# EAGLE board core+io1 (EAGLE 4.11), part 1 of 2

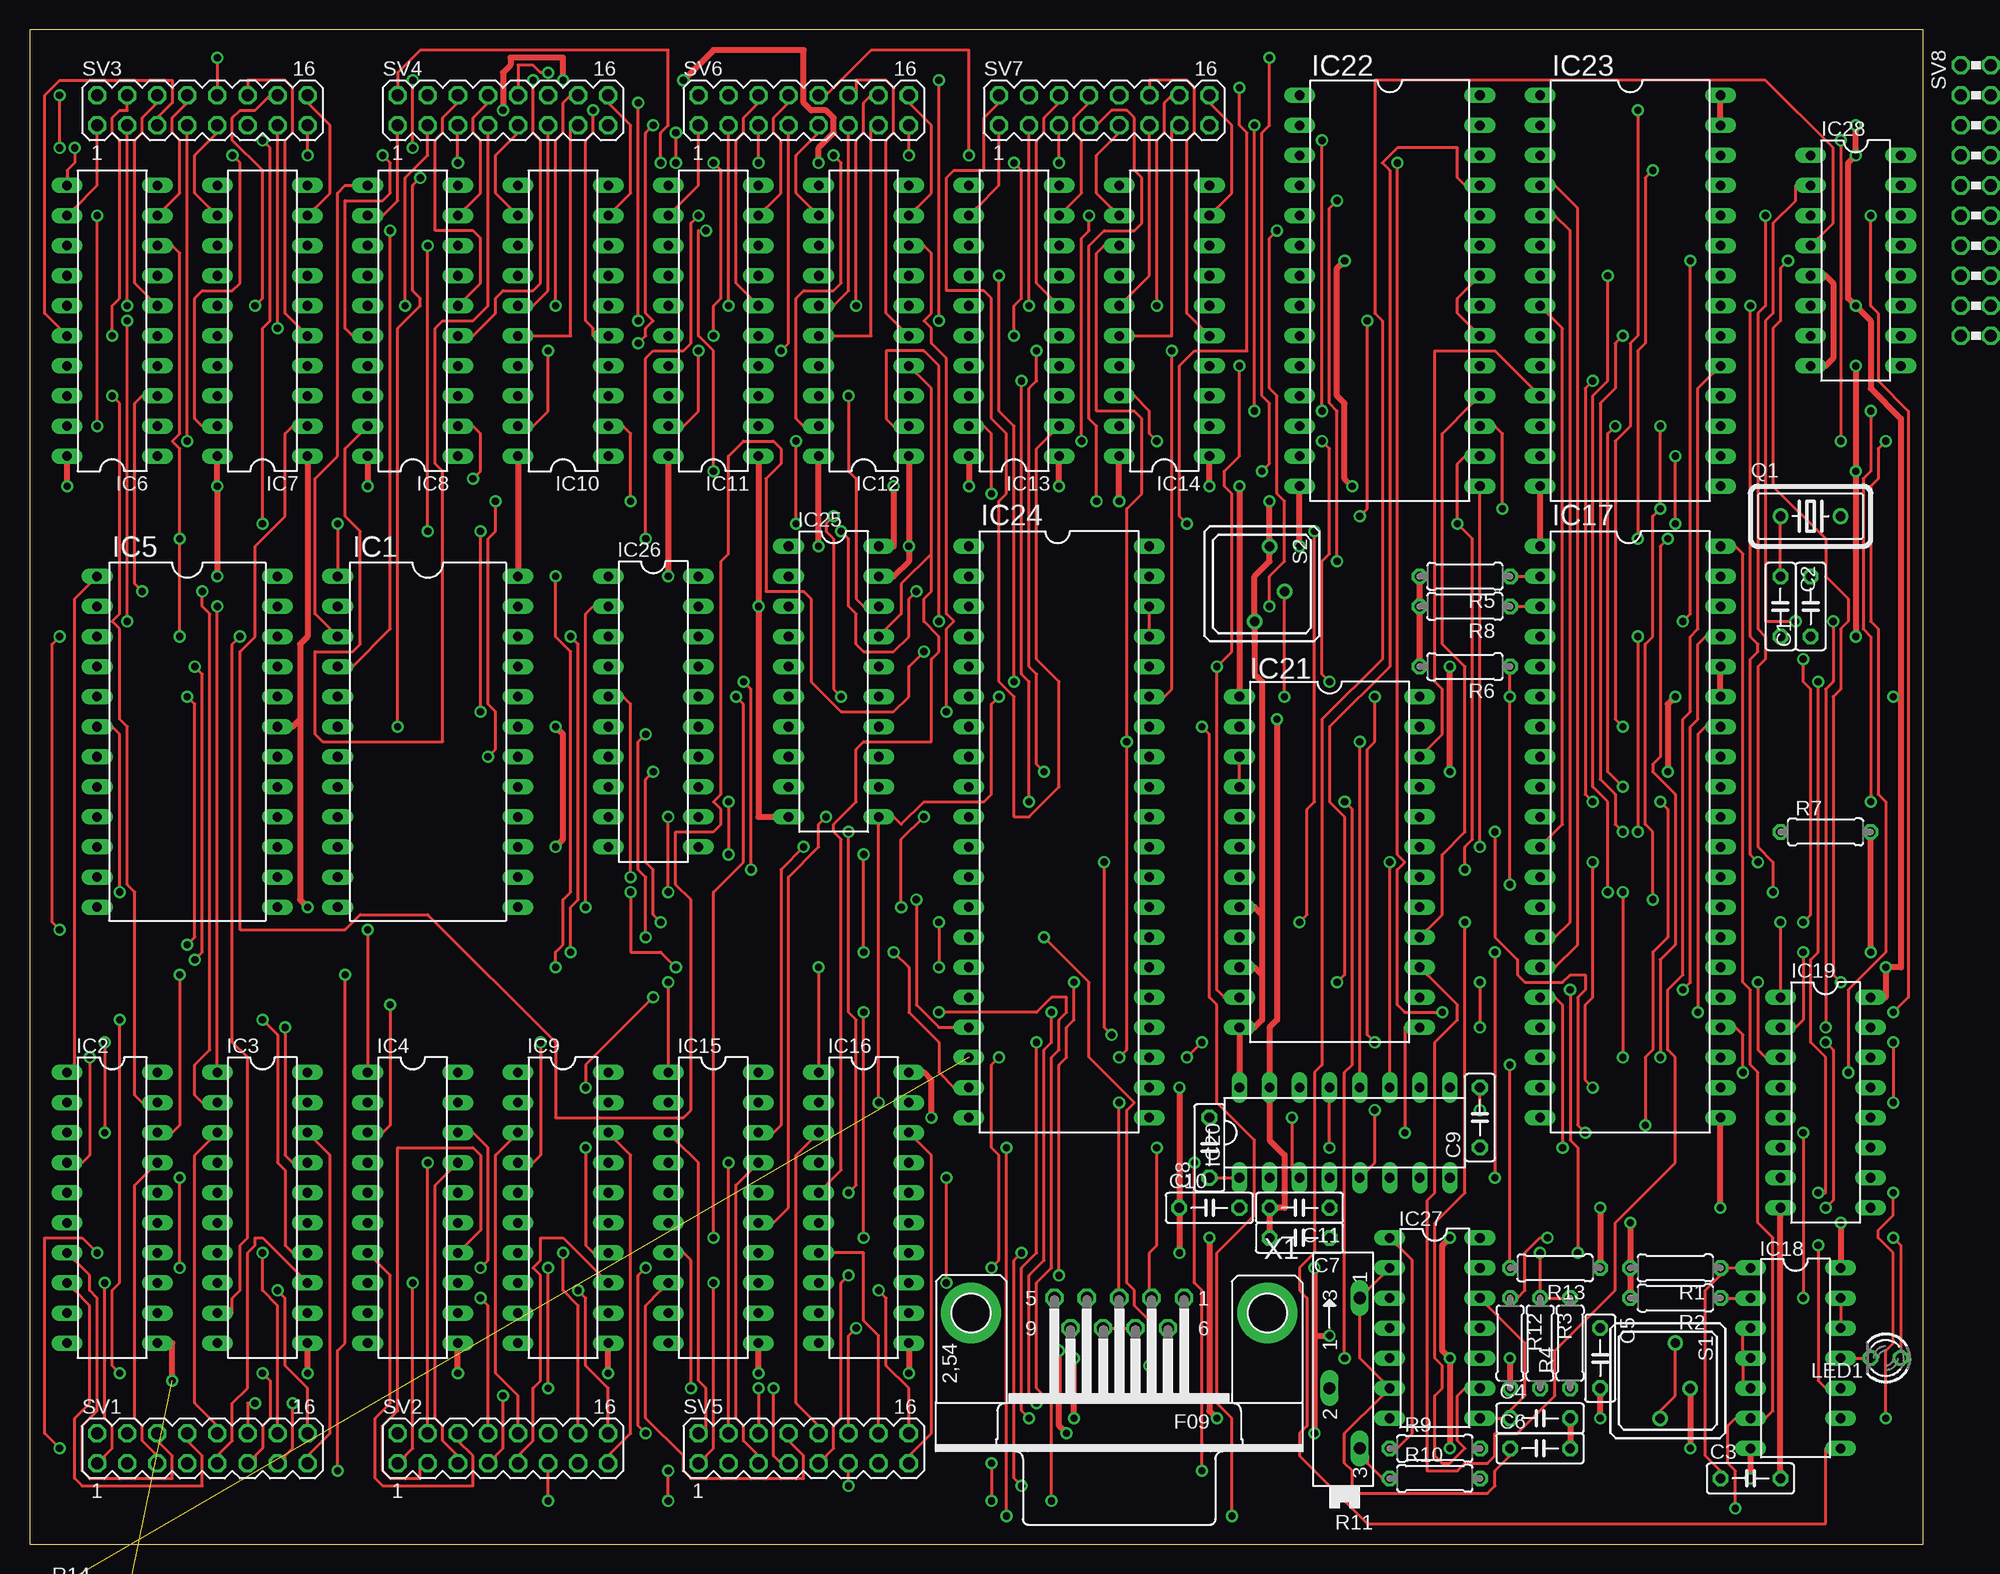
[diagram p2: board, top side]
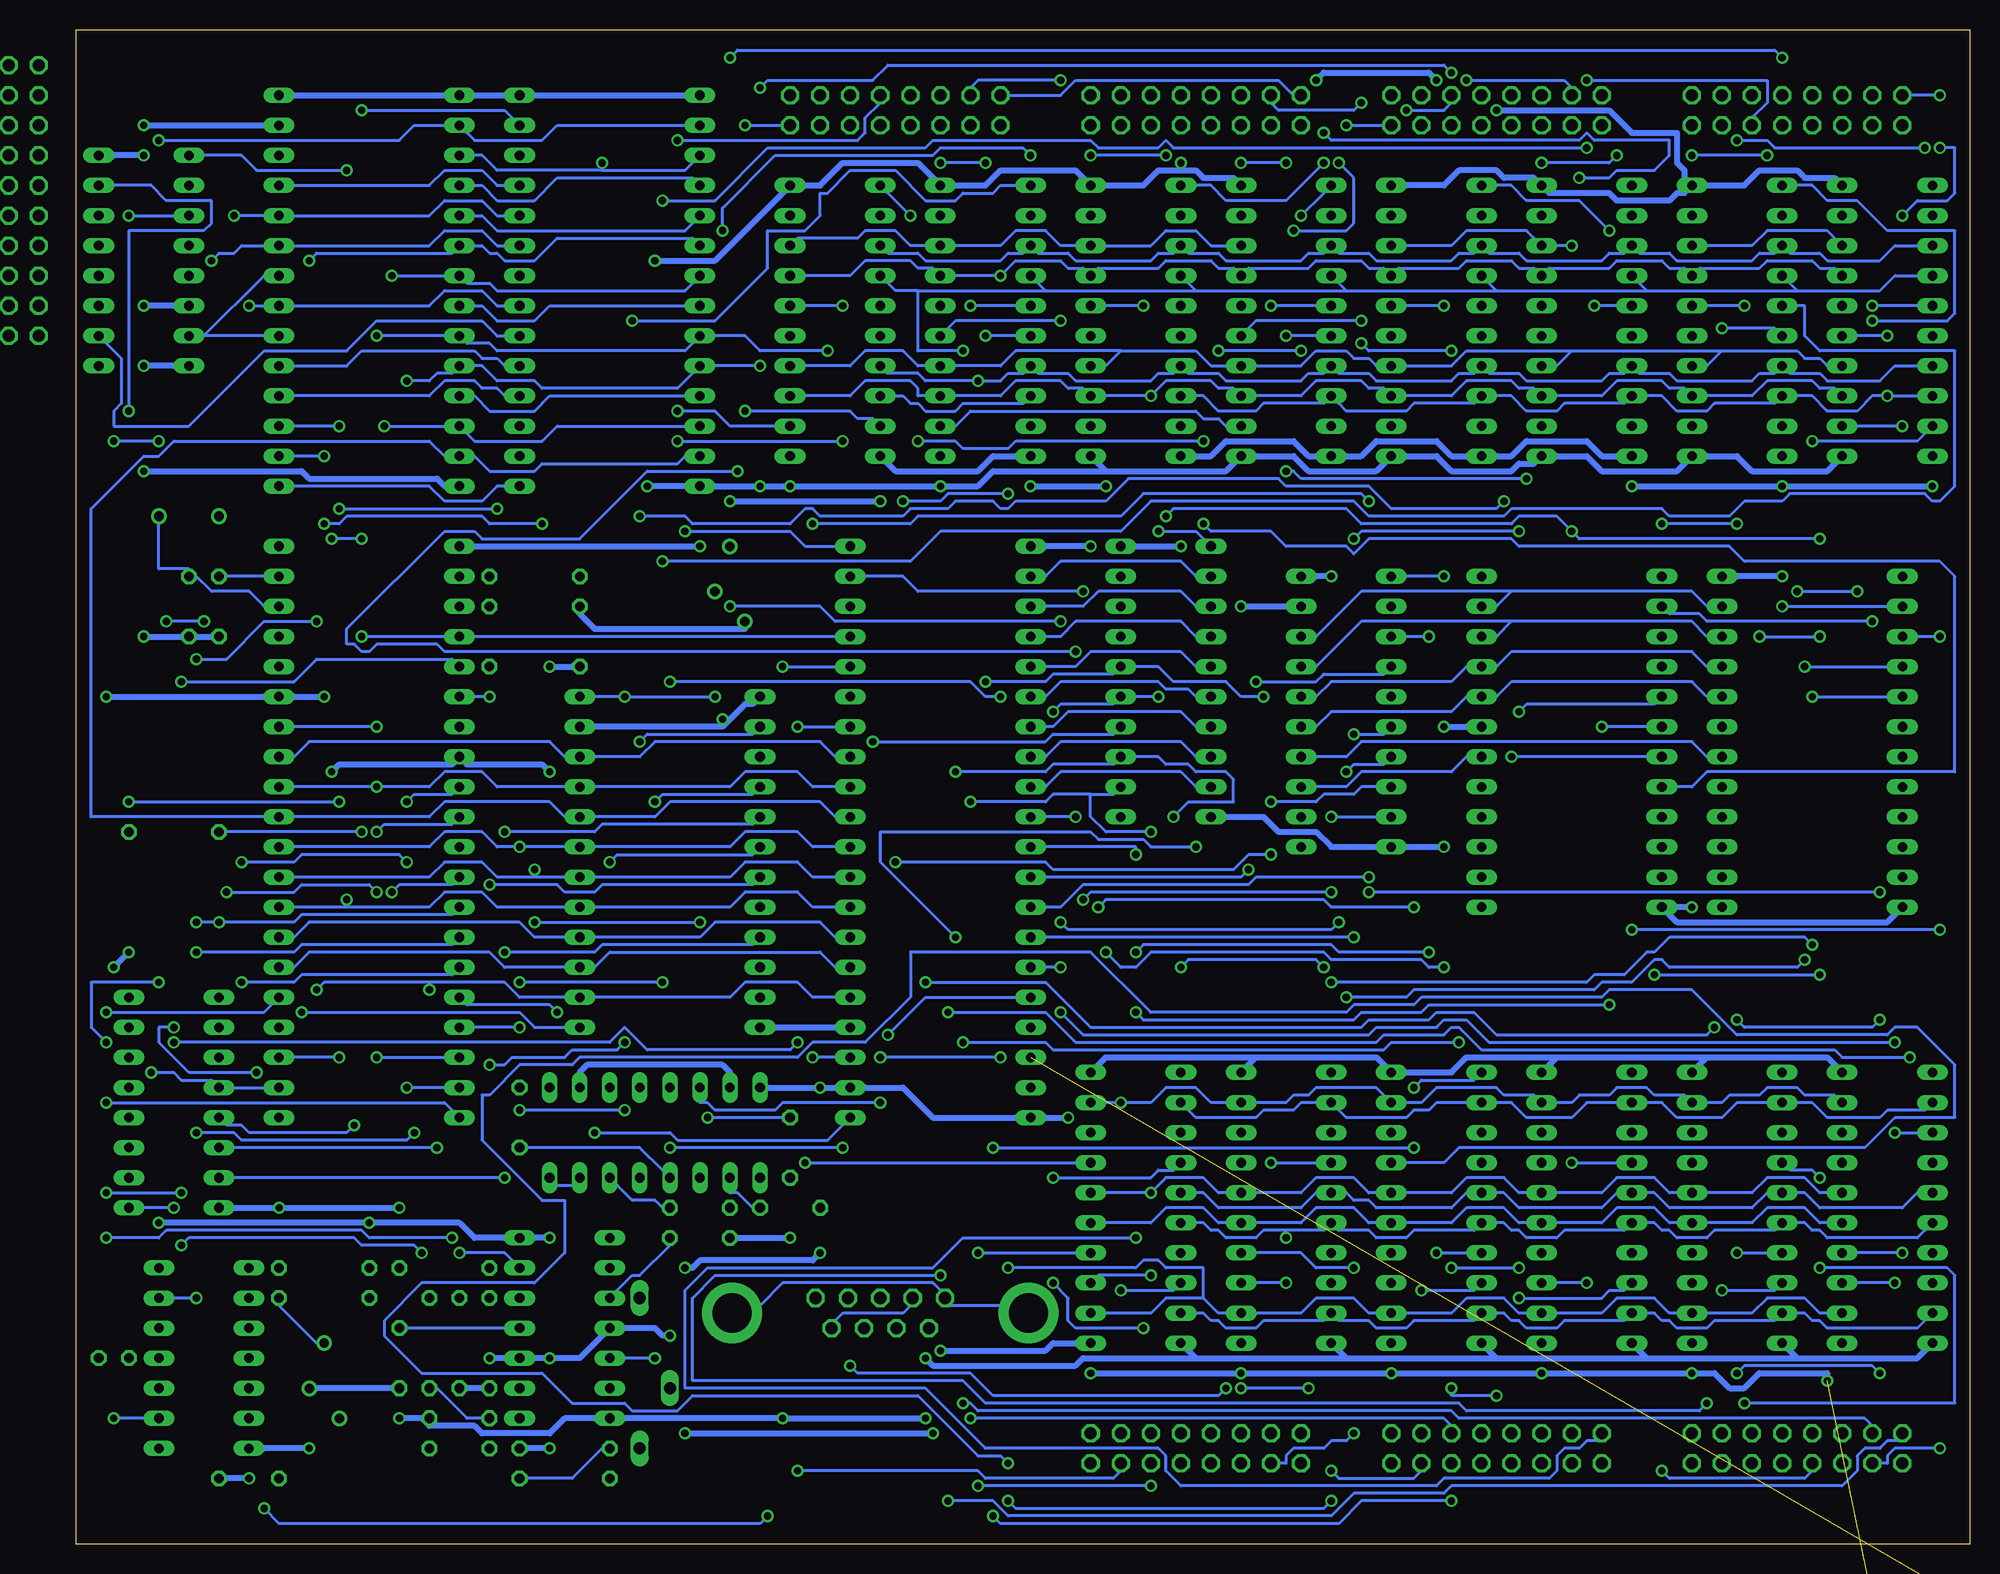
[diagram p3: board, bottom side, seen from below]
Size 160 x 127.94 mm. Coordinates in mm from the lower left corner, seen from the top.
Outline: 0,0 160,0 160,127.94 0,127.94 0,0
Copper layers (1*16): Top 0.035mm / dielectric 1.5mm / Bottom 0.035mm
Design rules "default": minimum track width 10mil, minimum drill 24mil, track to track 8mil, track to pad 8mil, pad to pad 8mil, via to via 8mil, smd to smd 8mil, copper to edge 40mil, drill to drill 8mil, minimum pad ring 10mil, minimum via ring 8mil, stop-mask expansion 4mil, vias tented up to drill 0mil, thermal gap 10mil
Net classes: 1 Power: width 0.508 mm, drill 0.254 mm, clearance 0.254 mm

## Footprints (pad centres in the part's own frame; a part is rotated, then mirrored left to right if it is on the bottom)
C050-025X075 = drill 0.813 octagon: 1 -2.54,0; 2 2.54,0
DIL24-6 = drill 0.813 long: 1 -13.97,-7.62; 2 -11.43,-7.62; 3 -8.89,-7.62; 4 -6.35,-7.62; 5 -3.81,-7.62; 6 -1.27,-7.62; 7 1.27,-7.62; 8 3.81,-7.62; 9 6.35,-7.62; 10 8.89,-7.62; 11 11.43,-7.62; 12 13.97,-7.62; 13 13.97,7.62; 14 11.43,7.62; 15 8.89,7.62; 16 6.35,7.62; 17 3.81,7.62; 18 1.27,7.62; 19 -1.27,7.62; 20 -3.81,7.62; 21 -6.35,7.62; 22 -8.89,7.62; 23 -11.43,7.62; 24 -13.97,7.62
DIL20 = drill 0.813 long: 1 -11.43,-3.81; 2 -8.89,-3.81; 3 -6.35,-3.81; 4 -3.81,-3.81; 5 -1.27,-3.81; 6 1.27,-3.81; 7 3.81,-3.81; 8 6.35,-3.81; 9 8.89,-3.81; 10 11.43,-3.81; 11 11.43,3.81; 12 8.89,3.81; 13 6.35,3.81; 14 3.81,3.81; 15 1.27,3.81; 16 -1.27,3.81; 17 -3.81,3.81; 18 -6.35,3.81; 19 -8.89,3.81; 20 -11.43,3.81
DIL40 = drill 0.813 long: 1 -24.13,-7.62; 2 -21.59,-7.62; 3 -19.05,-7.62; 4 -16.51,-7.62; 5 -13.97,-7.62; 6 -11.43,-7.62; 7 -8.89,-7.62; 8 -6.35,-7.62; 9 -3.81,-7.62; 10 -1.27,-7.62; 11 1.27,-7.62; 12 3.81,-7.62; 13 6.35,-7.62; 14 8.89,-7.62; 15 11.43,-7.62; 16 13.97,-7.62; 17 16.51,-7.62; 18 19.05,-7.62; 19 21.59,-7.62; 20 24.13,-7.62; 21 24.13,7.62; 22 21.59,7.62; 23 19.05,7.62; 24 16.51,7.62; 25 13.97,7.62; 26 11.43,7.62; 27 8.89,7.62; 28 6.35,7.62; 29 3.81,7.62; 30 1.27,7.62; 31 -1.27,7.62; 32 -3.81,7.62; 33 -6.35,7.62; 34 -8.89,7.62; 35 -11.43,7.62; 36 -13.97,7.62; 37 -16.51,7.62; 38 -19.05,7.62; 39 -21.59,7.62; 40 -24.13,7.62
DIL14 = drill 0.813 long: 1 -7.62,-3.81; 2 -5.08,-3.81; 3 -2.54,-3.81; 4 0,-3.81; 5 2.54,-3.81; 6 5.08,-3.81; 7 7.62,-3.81; 8 7.62,3.81; 9 5.08,3.81; 10 2.54,3.81; 11 0,3.81; 12 -2.54,3.81; 13 -5.08,3.81; 14 -7.62,3.81
DIL16 = drill 0.813 long: 1 -8.89,-3.81; 2 -6.35,-3.81; 3 -3.81,-3.81; 4 -1.27,-3.81; 5 1.27,-3.81; 6 3.81,-3.81; 7 6.35,-3.81; 8 8.89,-3.81; 9 8.89,3.81; 10 6.35,3.81; 11 3.81,3.81; 12 1.27,3.81; 13 -1.27,3.81; 14 -3.81,3.81; 15 -6.35,3.81; 16 -8.89,3.81
DIL24 = drill 0.813 long: 1 -13.97,-7.62; 2 -11.43,-7.62; 3 -8.89,-7.62; 4 -6.35,-7.62; 5 -3.81,-7.62; 6 -1.27,-7.62; 7 1.27,-7.62; 8 3.81,-7.62; 9 6.35,-7.62; 10 8.89,-7.62; 11 11.43,-7.62; 12 13.97,-7.62; 13 13.97,7.62; 14 11.43,7.62; 15 8.89,7.62; 16 6.35,7.62; 17 3.81,7.62; 18 1.27,7.62; 19 -1.27,7.62; 20 -3.81,7.62; 21 -6.35,7.62; 22 -8.89,7.62; 23 -11.43,7.62; 24 -13.97,7.62
DIL28 = drill 0.813 long: 1 -16.51,-7.62; 2 -13.97,-7.62; 3 -11.43,-7.62; 4 -8.89,-7.62; 5 -6.35,-7.62; 6 -3.81,-7.62; 7 -1.27,-7.62; 8 1.27,-7.62; 9 3.81,-7.62; 10 6.35,-7.62; 11 8.89,-7.62; 12 11.43,-7.62; 13 13.97,-7.62; 14 16.51,-7.62; 15 16.51,7.62; 16 13.97,7.62; 17 11.43,7.62; 18 8.89,7.62; 19 6.35,7.62; 20 3.81,7.62; 21 1.27,7.62; 22 -1.27,7.62; 23 -3.81,7.62; 24 -6.35,7.62; 25 -8.89,7.62; 26 -11.43,7.62; 27 -13.97,7.62; 28 -16.51,7.62
LED3MM = drill 0.813 octagon: A -1.27,0; K 1.27,0
HC18U-V = drill 0.813 round: 1 -2.54,0; 2 2.54,0
0207/7 = drill 0.813 octagon: 1 -3.81,0; 2 3.81,0
SP19L = drill 1.016 long: A 5.715,-1.27; E -6.985,-1.27; S -1.905,1.27
RDT1034 = drill 0.8 round: A 3.175,-0.635; A1 -3.175,0.635; B 0.65,1.9
MA08-2 = drill 1.016 octagon: 1 -8.89,-1.27; 2 -8.89,1.27; 3 -6.35,-1.27; 4 -6.35,1.27; 5 -3.81,-1.27; 6 -3.81,1.27; 7 -1.27,-1.27; 8 -1.27,1.27; 9 1.27,-1.27; 10 1.27,1.27; 11 3.81,-1.27; 12 3.81,1.27; 13 6.35,-1.27; 14 6.35,1.27; 15 8.89,-1.27; 16 8.89,1.27
MA10-2W = drill 1.016 octagon: 1 -11.43,-1.27; 2 -11.43,1.27; 3 -8.89,-1.27; 4 -8.89,1.27; 5 -6.35,-1.27; 6 -6.35,1.27; 7 -3.81,-1.27; 8 -3.81,1.27; 9 -1.27,-1.27; 10 -1.27,1.27; 11 1.27,-1.27; 12 1.27,1.27; 13 3.81,-1.27; 14 3.81,1.27; 15 6.35,-1.27; 16 6.35,1.27; 17 8.89,-1.27; 18 8.89,1.27; 19 11.43,-1.27; 20 11.43,1.27
F09HP = drill 1.016 octagon: 1 -5.486,-1.27; 2 -2.743,-1.27; 3 0,-1.27; 4 2.743,-1.27; 5 5.486,-1.27; 6 -4.115,1.27; 7 -1.372,1.27; 8 1.372,1.27; 9 4.115,1.27 | drill 3.302 pad 5.08 round: G1 -12.522,0; G2 12.522,0

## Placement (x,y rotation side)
C1  27pf  [C050-025X075]  150.49,79.21 90 top
C2  27pf  [C050-025X075]  147.95,79.21 270 top
C3  22uf  [C050-025X075]  145.41,5.55 0 top
C4  0.1uf  [C050-025X075]  127.63,10.63 0 top
C5  10uf  [C050-025X075]  132.71,15.71 270 top
C6  330pf  [C050-025X075]  127.63,8.09 0 top
C7  10uf  [C050-025X075]  107.31,25.87 180 top
C8  0.1uf  [C050-025X075]  99.69,33.49 90 top
C9  0.1uf  [C050-025X075]  122.55,36.03 90 top
C10  0.1uf  [C050-025X075]  99.69,28.41 0 top
C11  0.1uf  [C050-025X075]  107.31,28.41 180 top
IC1  74154N  [DIL24-6]  33.65,67.78 270 top
IC2  74LS373N  [DIL20]  6.98,28.41 270 top
IC3  74LS373N  [DIL20]  19.68,28.41 270 top
IC4  74LS373N  [DIL20]  32.38,28.41 270 top
IC5  74154N  [DIL24-6]  13.33,67.78 270 top
IC6  74LS374N  [DIL20]  6.98,103.34 90 top
IC7  74LS374N  [DIL20]  19.68,103.34 90 top
IC8  74LS374N  [DIL20]  32.38,103.34 90 top
IC9  74LS373N  [DIL20]  45.08,28.41 270 top
IC10  74LS374N  [DIL20]  45.08,103.34 90 top
IC11  74LS374N  [DIL20]  57.78,103.34 90 top
IC12  74LS374N  [DIL20]  70.48,103.34 90 top
IC13  74LS374N  [DIL20]  83.18,103.34 90 top
IC14  74LS374N  [DIL20]  95.88,103.34 90 top
IC15  74LS373N  [DIL20]  57.78,28.41 270 top
IC16  74LS373N  [DIL20]  70.48,28.41 270 top
IC17  [DIL40]  135.25,60.16 270 top
IC18  74LS00N  [DIL14]  149.22,15.71 270 top
IC19  74LS138N  [DIL16]  151.76,37.3 270 top
IC20  MAX232  [DIL16]  111.12,34.76 0 top
IC21  [DIL24]  109.85,57.62 270 top
IC22  5565  [DIL28]  114.93,105.88 270 top
IC23  2764  [DIL28]  135.25,105.88 270 top
IC24  [DIL40]  86.99,60.16 270 top
IC25  74LS245N  [DIL20]  67.94,72.86 270 top
IC26  74LS245N  [DIL20]  52.7,70.32 270 top
IC27  LM556N  [DIL14]  118.74,18.25 270 top
IC28  74LS138N  [DIL16]  154.3,108.42 270 top
LED1  [LED3MM]  156.84,15.71 180 top
Q1  4Mhz  [HC18U-V]  150.49,86.83 0 top
R1  10K  [0207/7]  139.06,23.33 180 top
R2  10K  [0207/7]  139.06,20.79 180 top
R3  100K  [0207/7]  127.63,16.98 270 top
R4  100K  [0207/7]  130.17,16.98 90 top
R5  3.3K  [0207/7]  121.28,81.75 180 top
R6  3.3K  [0207/7]  121.28,74.13 180 top
R7  3.3K  [0207/7]  151.76,60.16 0 top
R8  3.3K  [0207/7]  121.28,79.21 180 top
R9  1.8K  [0207/7]  118.74,8.09 0 top
R10  10K  [0207/7]  118.74,5.55 0 top
R11  10K  [SP19L]  111.12,15.08 90 top
R12  270  [0207/7]  125.09,16.98 270 top
R13  1K  [0207/7]  128.9,23.33 180 top
R14  3.3K  [0207/7]  not placed on the board
S1  RESET  [RDT1034]  138.42,13.81 270 top
S2  DEBUG  [RDT1034]  104.13,81.11 270 top
SV1  [MA08-2]  14.6,8.09 0 top
SV2  [MA08-2]  40,8.09 0 top
SV3  [MA08-2]  14.6,121.12 0 top
SV4  [MA08-2]  40,121.12 0 top
SV5  [MA08-2]  65.4,8.09 0 top
SV6  [MA08-2]  65.4,121.12 0 top
SV7  [MA08-2]  90.8,121.12 0 top
SV8  [MA10-2W]  not placed on the board
X1  [F09HP]  92.07,19.52 180 top

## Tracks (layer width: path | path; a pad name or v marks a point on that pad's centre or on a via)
A00  (via drill 0.61)
  Top 0.254: IC21.11 100.96,46.19 100.32,46.82 v100.32,74.13 101.59,75.4 101.59,88.73 100.96,89.37 100.96,90.64 102.23,91.91 v102.23,99.53 | v132.07,62.7 131.44,63.34 131.44,97.62 v132.07,98.26
  Bottom 0.254: v100.32,74.13 95.88,74.13 IC24.36 | v132.07,62.7 131.44,63.34 128.27,63.34 IC17.9 | v132.07,98.26 130.17,98.26 129.53,98.89 128.27,98.89 IC23.10 126.36,99.53 125.72,99.53 124.45,98.26 121.28,98.26 120.64,97.62 109.21,97.62 107.94,98.89 IC22.10 106.04,99.53 v102.23,99.53
A01  (via drill 0.61)
  Top 0.254: v96.52,100.8 96.52,72.22 95.88,71.59 IC24.35 | v134.62,60.16 133.98,60.8 133.98,63.34 132.71,64.61 132.71,96.36 133.98,97.62 133.98,101.44 v134.62,102.07
  Bottom 0.254: v96.52,100.8 102.23,100.8 103.5,102.07 106.04,102.07 IC22.9 107.94,101.44 108.58,100.8 124.45,100.8 125.09,101.44 126.99,101.44 IC23.9 128.9,102.07 v134.62,102.07 | v134.62,60.16 133.98,60.8 128.27,60.8 IC17.10
A02
  Top 0.254: IC17.11 128.27,59.52 129.53,60.8 129.53,102.7 128.27,103.97 IC23.8
  Bottom 0.254: IC22.8 108.58,104.61 120.01,104.61 121.28,103.34 124.45,103.34 125.72,104.61 126.36,104.61 IC23.8
A03  (via drill 0.61)
  Top 0.254: v133.34,55.08 133.34,62.7 132.07,63.97 132.07,96.99 133.34,98.26 v133.34,107.15
  Bottom 0.254: v133.34,55.08 132.71,55.71 128.27,55.71 IC17.12 | v133.34,107.15 128.9,107.15 IC23.7 126.99,106.52 125.09,106.52 124.45,105.88 108.58,105.88 107.94,106.52 IC22.7
A04  (via drill 0.61)
  Top 0.254: v147.95,52.54 147.95,46.82 IC19.1 | v140.33,108.42 140.33,78.58 v139.69,77.94 | v149.85,74.77 149.85,72.86 150.49,72.22 150.49,53.17 v149.85,52.54
  Bottom 0.254: IC22.6 107.94,110.33 119.38,110.33 121.28,108.42 123.82,108.42 124.45,109.05 125.09,109.05 125.72,109.69 126.36,109.69 IC23.6 128.27,109.05 139.69,109.05 v140.33,108.42 | IC17.13 128.27,53.17 140.97,53.17 141.6,52.54 v147.95,52.54 v149.85,52.54 | v139.69,77.94 144.14,77.94 147.31,74.77 v149.85,74.77
A05  (via drill 0.61)
  Top 0.254: IC23.5 128.9,112.23 130.17,110.96 130.17,52.54 128.9,51.27 IC17.14 | v149.85,50 149.85,44.28 149.22,43.65 IC19.2
  Bottom 0.254: v149.85,50 141.6,50 140.97,50.63 128.27,50.63 IC17.14 | IC22.5 107.94,111.59 108.58,110.96 124.45,110.96 125.72,112.23 126.36,112.23 IC23.5
A06  (via drill 0.61)
  Top 0.254: IC23.4 128.9,114.77 130.81,112.86 130.81,50.63 128.9,48.73 IC17.15 | v146.04,47.46 146.04,41.74 146.68,41.11 IC19.3
  Bottom 0.254: v146.04,47.46 141.6,47.46 140.97,48.09 128.27,48.09 IC17.15 | IC22.4 107.94,115.41 119.38,115.41 121.28,113.5 124.45,113.5 125.72,114.77 126.36,114.77 IC23.4
A07  (via drill 0.61)
  Top 0.254: v129.53,33.49 129.53,45.55 128.9,46.19 IC17.16 | v115.56,116.67 115.56,58.25 116.2,57.62 115.56,56.98 115.56,45.55 116.2,44.92 v119.38,44.92
  Bottom 0.254: 115.56,116.04 124.45,116.04 125.72,117.31 126.36,117.31 IC23.3 | 115.56,116.04 108.58,116.04 107.94,116.67 IC22.3 | v129.53,33.49 146.68,33.49 IC19.6 | v115.56,116.67 115.56,116.04 | v119.38,44.92 120.01,45.55 126.99,45.55 IC17.16
A08  (via drill 0.61)
  Top 0.254: v122.55,47.46 v122.55,43.65 | v110.48,47.46 111.12,48.09 111.12,61.43 109.85,62.7 109.85,69.05 114.93,74.13 114.93,116.04 114.3,116.67 115.56,117.94 120.64,117.94 120.64,115.41 121.28,114.77 IC22.25
  Bottom 0.254: IC23.25 141.6,114.77 130.17,114.77 128.9,116.04 125.72,116.04 124.45,114.77 123.82,114.77 IC22.25 | v122.55,43.65 126.36,43.65 IC17.17 | v110.48,47.46 v122.55,47.46
A09  (via drill 0.61)
  Top 0.254: v134.62,55.08 v134.62,41.11 | v147.31,55.08 147.31,57.62 146.04,58.89 146.04,74.13 146.68,74.77 146.68,76.67 146.04,77.3 146.04,103.97 146.68,104.61 v146.68,112.23
  Bottom 0.254: IC22.24 123.82,112.23 124.45,112.23 125.72,113.5 128.9,113.5 130.17,112.23 141.6,112.23 IC23.24 144.14,112.23 v146.68,112.23 | v134.62,41.11 128.9,41.11 IC17.18 | v134.62,55.08 135.25,55.71 140.97,55.71 141.6,55.08 v147.31,55.08
A10  (via drill 0.61)
  Top 0.254: v132.07,38.57 131.44,39.2 131.44,45.55 132.07,46.19 v132.07,57.62 | v146.04,57.62 145.41,58.25 145.41,74.77 146.04,75.4 146.04,76.03 145.41,76.67 v145.41,104.61
  Bottom 0.254: IC22.21 123.82,104.61 124.45,104.61 125.72,105.88 128.9,105.88 130.17,104.61 141.6,104.61 IC23.21 144.14,104.61 v145.41,104.61 | v132.07,38.57 128.9,38.57 IC17.19 | v132.07,57.62 132.71,58.25 140.97,58.25 141.6,57.62 v146.04,57.62
A11  (via drill 0.61)
  Top 0.254: v157.47,42.38 v157.47,37.3 | v153.03,47.46 152.39,48.09 152.39,71.59 153.03,72.22 153.03,77.3 153.66,77.94 153.66,79.84 151.76,81.75 151.76,84.92 147.31,89.37 147.31,102.7 147.95,103.34 147.95,107.78 v148.59,108.42
  Bottom 0.254: IC22.23 123.82,109.69 124.45,109.69 125.72,110.96 128.9,110.96 130.17,109.69 141.6,109.69 IC23.23 144.14,109.69 146.04,109.69 146.68,109.05 147.95,109.05 v148.59,108.42 | v157.47,37.3 128.9,37.3 128.27,36.66 IC17.20 | v157.47,42.38 158.75,43.65 158.75,47.46 v153.03,47.46
A12  (via drill 0.61)
  Top 0.254: v153.66,39.84 153.66,46.82 156.84,50 156.84,62.7 156.2,63.34 156.2,77.3 155.57,77.94 155.57,89.37 156.2,90 156.2,92.55 v156.84,93.18 | v153.03,118.58 v153.03,93.18
  Bottom 0.254: IC17.22 144.14,38.57 146.68,38.57 IC19.4 148.59,39.2 151.12,39.2 151.76,39.84 v153.66,39.84 | IC22.2 108.58,119.85 119.38,119.85 120.64,118.58 126.36,118.58 126.99,119.22 IC23.2 128.9,119.85 131.44,119.85 132.71,118.58 v153.03,118.58 | v153.03,93.18 v156.84,93.18
A13  (via drill 0.61)
  Top 0.254: v137.79,41.11 137.79,49.37 139.06,50.63 139.06,63.34 137.16,65.24 137.16,65.88 137.79,66.51 137.79,84.29 v138.42,84.92 | v135.88,84.92 135.88,100.8 136.52,101.44 136.52,115.41 v137.16,116.04
  Bottom 0.254: v137.79,41.11 141.6,41.11 IC17.23 | v135.88,84.92 v138.42,84.92 | v137.16,116.04 144.78,116.04 146.04,117.31 149.22,117.31 IC28.1
A14  (via drill 0.61)
  Top 0.254: v144.78,39.84 144.78,43.02 144.14,43.65 IC17.24 | v151.76,43.65 151.76,72.22 152.39,72.86 v152.39,77.94 | v149.22,77.94 146.68,77.94 146.68,103.34 147.31,103.97 147.31,111.59 149.22,113.5 149.22,114.77 IC28.2
  Bottom 0.254: v144.78,39.84 150.49,39.84 153.03,42.38 153.03,43.65 v151.76,43.65 | v149.22,77.94 v152.39,77.94
A15  (via drill 0.61)
  Top 0.254: v157.47,44.92 158.75,46.19 158.75,95.72 156.2,98.26 156.2,103.97 155.57,104.61 v155.57,112.23
  Bottom 0.254: v157.47,44.92 144.14,44.92 143.5,45.55 IC17.25 | v155.57,112.23 151.76,112.23 IC28.3
AB\
  Top 0.254: IC22.20 121.91,102.7 120.64,103.97 120.64,105.25 121.91,106.52 IC22.22
  Bottom 0.254: IC28.10 157.47,101.44 156.2,100.16 156.2,96.36 156.84,95.72 156.84,94.45 150.49,94.45 144.14,100.8 137.16,100.8 134.62,103.34 125.72,103.34 124.45,102.07 123.82,102.07 IC22.20
CB1  (1 unrouted)
D0
  Top 0.254: IC23.11 126.99,97.62 123.82,100.8 118.74,100.8 118.74,72.86 119.38,72.22 119.38,68.41 118.1,67.14 IC21.22
  Bottom 0.254: IC22.11 108.58,96.99 120.01,96.99 121.28,95.72 125.09,95.72 126.36,96.99 IC23.11 | IC24.33 95.88,66.51 97.15,67.78 111.12,67.78 112.39,66.51 116.2,66.51 IC21.22 118.74,66.51 120.01,67.78 140.33,67.78 141.6,66.51 IC17.33
D1  (via drill 0.61)
  Top 0.254: v133.98,94.45 133.34,93.81 133.34,65.24 v134.62,63.97
  Bottom 0.254: IC22.12 108.58,94.45 119.38,94.45 120.64,93.18 126.36,93.18 126.99,93.81 IC23.12 128.9,94.45 v133.98,94.45 | IC24.32 95.88,63.97 97.78,63.97 99.05,65.24 103.5,65.24 104.77,63.97 116.2,63.97 IC21.21 118.74,63.97 124.45,63.97 125.72,65.24 128.9,65.24 130.17,63.97 v134.62,63.97 141.6,63.97 IC17.32
D2
  Bottom 0.254: IC22.13 108.58,91.91 109.21,91.28 120.64,91.28 121.28,90.64 125.09,90.64 126.36,91.91 IC23.13 128.9,91.91 130.17,93.18 151.76,93.18 153.03,91.91 154.3,91.91 158.75,87.47 158.75,61.43 144.14,61.43 IC17.31 141.6,61.43 130.17,61.43 128.9,62.7 120.01,62.7 118.74,61.43 IC21.20 116.2,61.43 111.12,61.43 109.85,62.7 97.15,62.7 95.88,61.43 IC24.31
D3  (via drill 0.61)
  Top 0.254: v122.55,58.89 122.55,88.73 IC22.15
  Bottom 0.254: IC23.15 141.6,89.37 130.17,89.37 128.9,88.1 125.72,88.1 124.45,89.37 123.82,89.37 IC22.15 | IC24.30 95.88,58.89 97.78,58.89 99.05,60.16 103.5,60.16 104.77,58.89 116.2,58.89 IC21.19 118.74,58.89 v122.55,58.89 124.45,58.89 125.72,60.16 128.9,60.16 130.17,58.89 141.6,58.89 IC17.30
D4  (via drill 0.61)
  Top 0.254: v139.06,86.19 v139.06,91.91 | IC22.16 121.28,91.91 120.64,91.28 v120.64,86.19 121.91,84.92 121.91,59.52 121.28,58.89 v121.28,56.98
  Bottom 0.254: v120.64,86.19 125.09,86.19 125.72,86.83 137.16,86.83 137.79,86.19 v139.06,86.19 | v139.06,91.91 141.6,91.91 IC23.16 | IC24.29 95.88,56.35 97.78,56.35 99.05,57.62 103.5,57.62 104.77,56.35 116.2,56.35 IC21.18 118.74,56.35 121.28,56.35 | 121.28,56.35 124.45,56.35 125.72,57.62 128.9,57.62 130.17,56.35 141.6,56.35 IC17.29 | 121.28,56.35 v121.28,56.98
D5  (via drill 0.61)
  Top 0.254: v124.45,87.47 124.45,93.81 123.82,94.45 IC22.17 | v137.79,94.45 v137.79,87.47 137.16,86.83 137.16,76.67 136.52,76.03 136.52,60.8 137.16,60.16 v137.16,54.45
  Bottom 0.254: v137.79,87.47 v124.45,87.47 | v137.79,94.45 141.6,94.45 IC23.17 | IC24.28 95.88,53.81 97.78,53.81 99.05,55.08 103.5,55.08 104.77,53.81 116.2,53.81 IC21.17 118.74,53.81 124.45,53.81 125.72,55.08 128.9,55.08 130.17,53.81 137.16,53.81 | 137.16,53.81 141.6,53.81 IC17.28 | 137.16,53.81 v137.16,54.45
D6
  Top 0.254: IC22.18 121.91,96.36 119.38,93.81 119.38,76.03 121.28,74.13 121.28,60.16 119.38,58.25 119.38,53.17 118.1,51.91 IC21.16
  Bottom 0.254: IC22.18 123.82,96.99 124.45,97.62 125.72,97.62 126.36,98.26 128.9,98.26 130.17,96.99 141.6,96.99 IC23.18 | IC24.27 95.88,51.27 97.15,52.54 106.04,52.54 107.31,51.27 116.2,51.27 IC21.16 118.74,51.27 121.28,51.27 122.55,52.54 140.33,52.54 141.6,51.27 IC17.27
D7
  Top 0.254: IC23.19 142.23,98.89 140.97,97.62 140.97,77.3 140.33,76.67 140.33,70.32 139.69,69.69 139.69,48.09 138.42,46.82 138.42,41.74 139.06,41.11 139.06,32.22 133.98,27.14 133.98,21.42 128.9,16.34 128.9,12.54 125.72,9.36 123.82,9.36 123.82,7.46 123.19,6.82 121.28,6.82 120.64,6.18 118.1,6.18 118.1,29.04 118.74,29.68 118.74,42.38 120.64,44.28 120.64,45.55 118.1,48.09 IC21.15
  Bottom 0.254: IC22.19 123.82,99.53 124.45,100.16 125.72,100.16 126.36,100.8 135.88,100.8 137.16,99.53 141.6,99.53 IC23.19 | IC24.26 95.88,48.73 97.15,50 114.93,50 116.2,48.73 IC21.15 118.74,48.73 123.82,48.73 125.09,50 140.33,50 141.6,48.73 IC17.26
E  (via drill 0.61)
  Top 0.254: v151.12,25.23 151.12,13.81 151.76,13.17 IC18.10 | v130.81,24.6 130.81,33.49 130.17,34.12 v130.17,46.82 | v139.69,46.82 140.33,47.46 140.33,69.05 140.97,69.69 140.97,76.03 141.6,76.67 IC17.37
  Bottom 0.254: IC24.25 95.88,46.19 97.78,46.19 99.05,47.46 103.5,47.46 104.77,46.19 116.2,46.19 IC21.14 118.74,46.19 122.55,46.19 123.82,47.46 130.17,47.46 | v151.12,25.23 150.49,25.87 136.52,25.87 135.88,25.23 131.44,25.23 v130.81,24.6 | 130.17,47.46 v130.17,46.82 | v139.69,46.82 139.06,47.46 130.17,47.46
EF\
  Bottom 0.254: 149.22,102.07 144.14,102.07 IC23.20 | 149.22,102.07 IC28.7 149.22,102.07 | 149.22,102.07 144.14,107.15 IC23.22
GND  (via drill 0.61)
  Top 0.508: 22.86,69.69 22.22,69.05 IC5.19 | 22.86,69.69 22.86,76.03 23.49,76.67 23.49,91.28 IC7.1 | v23.49,53.81 22.86,54.45 22.86,69.69 | IC25.19 73.02,81.75 74.29,83.02 v74.29,84.29 74.29,91.28 IC12.1 | v44.45,58.89 45.08,59.52 45.08,68.41 v44.45,69.05 | IC11.1 61.59,91.28 v61.59,79.21 61.59,61.43 62.86,61.43 IC25.10 | v40,121.12 40,124.3 40.64,124.93 40.64,125.56 45.08,125.56 v45.08,123.66 | v55.24,123.66 57.78,126.2 65.4,126.2 65.4,121.75 66.03,121.12 67.3,121.12 67.94,120.48 67.94,119.22 66.67,117.94 v66.67,116.67 | v145.41,5.55 145.41,7.46 IC18.7 | C6.2 130.17,8.73 130.17,10 C4.2 | v132.71,10.63 132.71,12.54 C5.2 | v140.33,8.09 140.33,12.54 S1.B | v132.71,28.41 132.71,23.96 R13.1 | v142.87,28.41 142.87,35.39 IC17.21 | C3.2 147.95,6.18 147.95,27.77 IC19.8 | C7.2 104.77,26.5 104.77,27.77 C11.2 105.41,28.41 106.04,28.41 106.04,32.85 104.77,34.12 104.77,37.3 IC20.15 104.77,39.84 104.77,43.65 105.41,44.28 v105.41,69.69 | v100.32,10.63 99.69,11.27 v99.69,25.87 | IC28.8 151.76,99.53 152.39,100.16 152.39,106.52 151.76,107.15 IC28.5 | v154.3,99.53 v154.3,90.64 v154.3,76.67 | IC17.1 127.63,84.92 127.63,88.73 IC23.14 | v99.69,89.37 99.69,91.28 IC14.1 | v86.99,89.37 86.99,91.28 IC13.1 | v102.23,89.37 102.23,72.22 IC21.1 | v107.31,84.29 107.31,88.73 IC22.14 | v88.26,10.63 v88.26,15.71 | v111.12,108.42 110.48,107.78 110.48,96.99 111.12,96.36 111.12,90 v111.75,89.37
  Bottom 0.508: IC5.12 6.34,53.17 6.98,52.54 24.76,52.54 25.39,53.17 IC1.12 24.76,53.81 v23.49,53.81 | IC6.1 11.43,91.28 12.06,90.64 18.41,90.64 19.68,91.91 22.22,91.91 IC7.1 24.12,91.28 24.76,90.64 31.11,90.64 32.38,91.91 34.92,91.91 IC8.1 36.83,91.28 38.1,91.28 38.73,90.64 43.81,90.64 45.08,91.91 47.62,91.91 IC10.1 49.53,91.28 50.16,90.64 55.88,90.64 57.15,91.91 60.32,91.91 IC11.1 62.23,91.28 62.86,90.64 73.02,90.64 | v74.29,84.29 78.1,84.29 IC24.1 | v44.45,58.89 47.62,58.89 IC26.10 50.16,58.89 53.97,58.89 55.24,60.16 58.41,60.16 59.69,61.43 62.86,61.43 IC25.10 | v44.45,69.05 42.54,69.05 IC1.19 | v61.59,79.21 57.78,79.21 IC26.19 | 73.02,90.64 73.66,91.28 IC12.1 | IC10.10 47.62,114.77 44.45,114.77 43.18,116.04 40,116.04 39.37,115.41 36.83,115.41 IC8.10 35.55,114.14 30.47,114.14 29.84,113.5 25.39,113.5 24.76,114.14 24.12,114.14 IC7.10 | IC6.10 11.43,115.41 13.97,115.41 14.6,116.04 17.77,116.04 19.04,114.77 22.22,114.77 IC7.10 | 66.67,116.04 68.57,116.04 69.84,114.77 73.02,114.77 IC12.10 74.92,115.41 75.56,116.04 81.91,116.04 83.18,114.77 85.72,114.77 IC13.10 87.62,115.41 88.89,116.67 95.24,116.67 97.15,114.77 98.42,114.77 IC14.10 100.32,114.14 106.04,108.42 v111.12,108.42 | 66.67,116.04 65.4,116.04 64.77,115.41 62.23,115.41 IC11.10 | v40,121.12 30.47,121.12 28.57,119.22 24.76,119.22 24.76,116.67 24.12,116.04 24.12,115.41 IC7.10 | v45.08,123.66 45.72,124.3 54.61,124.3 v55.24,123.66 | 66.67,116.04 v66.67,116.67 | 14.6,15.71 4.44,15.71 3.8,16.34 IC2.10 | 14.6,15.71 15.24,16.34 IC3.10 | 27.3,15.71 27.93,16.34 IC4.10 | 27.3,15.71 14.6,15.71 | 40,15.71 40.64,16.34 IC9.10
  Bottom 0.508: 40,15.71 27.3,15.71 | 52.7,15.71 53.34,16.34 IC15.10 | 52.7,15.71 40,15.71 | 65.4,15.71 66.03,16.34 IC16.10 | 65.4,15.71 52.7,15.71 | v145.41,5.55 147.31,5.55 C3.2 | S1.B 139.69,13.17 133.34,13.17 C5.2 | v132.71,10.63 130.81,10.63 C4.2 130.17,10 126.36,10 125.72,9.36 120.01,9.36 118.74,10.63 116.2,10.63 IC27.7 113.66,10.63 v100.32,10.63 v88.26,10.63 | v140.33,8.09 144.14,8.09 IC18.7 | v132.71,28.41 v142.87,28.41 146.68,28.41 IC19.8 | IC20.15 104.77,39.84 105.41,40.48 116.83,40.48 117.47,39.84 IC20.10 | v99.69,25.87 104.13,25.87 C7.2 | C2.2 148.59,76.67 149.85,76.67 C1.1 151.12,76.67 v154.3,76.67 | v154.3,99.53 151.76,99.53 IC28.8 | 104.77,69.69 103.5,70.95 102.86,70.95 IC21.1 | 104.77,69.69 105.41,69.05 116.2,69.05 IC21.23 | v107.31,84.29 126.36,84.29 IC17.1 | v154.3,90.64 140.97,90.64 140.33,90 129.53,90 128.9,89.37 IC23.14 | 104.77,69.69 v105.41,69.69 | 65.4,15.71 74.92,15.71 75.56,15.08 87.62,15.08 v88.26,15.71 | v111.75,89.37 108.58,89.37 IC22.14 106.04,89.37 v102.23,89.37 v99.69,89.37 v86.99,89.37 83.81,89.37 82.55,90.64 73.02,90.64
HLT\
  Top 0.254: R5.1 125.72,81.75 126.36,81.75 IC17.2
IN00
  Top 0.254: IC2.1 3.8,40.48 3.8,79.84 5.08,81.11 IC5.1
IN01  (via drill 0.61)
  Top 0.254: v15.87,79.21 15.87,40.48 IC3.1
  Bottom 0.254: v15.87,79.21 6.98,79.21 IC5.2
IN02  (via drill 0.61)
  Top 0.254: v28.57,51.91 28.57,40.48 IC4.1 | v2.54,51.91 1.9,52.54 1.9,76.03 v2.54,76.67
  Bottom 0.254: v2.54,51.91 v28.57,51.91 | v2.54,76.67 4.44,76.67 IC5.3
IN03  (via drill 0.61)
  Top 0.254: v46.98,38.57 46.98,40.48 v52.7,46.19 | v13.97,49.37 14.6,50 14.6,73.5 v13.97,74.13
  Bottom 0.254: v46.98,38.57 46.35,39.2 41.91,39.2 IC9.1 | v52.7,46.19 47.62,46.19 46.98,46.82 31.74,46.82 31.11,47.46 28.57,47.46 26.66,49.37 26.03,49.37 25.39,48.73 14.6,48.73 v13.97,49.37 | v13.97,74.13 6.98,74.13 IC5.4
IN04  (via drill 0.61)
  Top 0.254: v13.33,71.59 13.97,70.95 13.97,51.27 v13.33,50.63 | v53.97,47.46 53.97,40.48 IC15.1
  Bottom 0.254: v13.33,71.59 6.98,71.59 IC5.5 | v13.33,50.63 13.97,51.27 25.39,51.27 26.66,50 27.3,50 29.2,48.09 31.74,48.09 32.38,47.46 v53.97,47.46
IN05  (via drill 0.61)
  Top 0.254: v66.67,48.73 66.67,40.48 IC16.1 | v54.61,48.73 53.34,50 50.8,50 v50.8,55.08 | v7.62,55.08 7.62,68.41 6.98,69.05 IC5.6
  Bottom 0.254: v66.67,48.73 66.03,49.37 55.24,49.37 v54.61,48.73 | v7.62,55.08 v50.8,55.08
IO-E\  (via drill 0.61)
  Top 0.254: v97.78,41.11 v99.05,42.38 | v151.76,42.38 152.39,41.74 152.39,29.04 v151.76,28.41
  Bottom 0.254: v97.78,41.11 95.88,41.11 IC24.23 | v99.05,42.38 99.69,41.74 111.75,41.74 113.66,43.65 114.93,42.38 v151.76,42.38 | v151.76,28.41 154.3,28.41 IC19.9
IO-F\  (via drill 0.61)
  Top 0.254: v123.82,50 v123.82,30.95
  Bottom 0.254: v123.82,50 116.2,50 115.56,50.63 102.86,50.63 IC21.9 | v123.82,30.95 146.68,30.95 IC19.7
IRQ\  (via drill 0.61)
  Top 0.254: IC24.37 94.61,77.3 94.61,78.58 IC24.38 | v135.88,76.67 v135.88,60.16
  Bottom 0.254: IC24.37 95.88,76.67 126.36,76.67 IC17.4 128.9,76.67 v135.88,76.67 | v135.88,60.16 147.31,60.16 R7.1
MR
  Top 0.254: R8.1 125.72,79.21 126.36,79.21 IC17.3
N$1
  Top 0.254: IC3.3 15.24,34.12 13.97,32.85 13.97,11.9 15.87,10 SV1.10
N$2  (via drill 0.61)
  Top 0.254: v12.7,23.33 v12.7,30.95 | v19.04,11.9 18.41,11.9 18.41,10 SV1.12
  Bottom 0.254: v12.7,30.95 13.33,31.58 15.24,31.58 IC3.4 | v12.7,23.33 1.9,23.33 1.27,22.7 1.27,11.9 v19.04,11.9
N$3
  Top 0.254: Q1.1 147.95,86.19 147.95,82.39 C2.1
  Bottom 0.254: IC17.39 144.14,81.75 147.31,81.75 C2.1
N$4
  Bottom 0.254: IC17.38 144.14,79.21 145.41,80.48 148.59,80.48 149.85,81.75 C1.2 150.49,82.39 153.03,82.39 153.03,86.19 Q1.2
N$5
  Bottom 0.254: IC25.2 65.4,81.75 66.67,83.02 76.83,83.02 78.1,81.75 IC24.2
N$6
  Top 0.254: IC18.5 144.78,13.81 144.78,15.08 IC18.4 144.78,16.34 144.78,17.61 IC18.3
N$7  (via drill 0.61)
  Top 0.254: v19.68,24.6 19.68,21.42 20.95,20.15 20.95,10 SV1.14
  Bottom 0.254: v19.68,24.6 17.14,24.6 IC3.7
N$8  (via drill 0.61)
  Top 0.254: v20.95,21.42 21.58,20.79 21.58,15.08 23.49,13.17 23.49,10 SV1.16
  Bottom 0.254: v20.95,21.42 16.5,21.42 IC3.8
N$9
  Top 0.254: IC2.8 3.8,21.42 5.08,20.15 5.08,11.9 3.8,10.63 3.8,5.55 4.44,4.92 14.6,4.92 14.6,7.46 13.33,8.73 SV1.8
N$10
  Top 0.254: IC2.7 3.8,23.96 5.08,22.7 5.08,21.42 5.71,20.79 5.71,11.27 4.44,10 4.44,6.18 5.08,5.55 12.06,5.55 12.06,7.46 10.79,8.73 SV1.6
N$11  (via drill 0.61)
  Top 0.254: v5.08,41.11 5.08,32.85 4.44,32.22 IC2.4 | v86.35,44.92 86.35,42.38 85.72,41.74 85.72,23.96 84.45,22.7 84.45,12.54 v85.08,11.9
  Bottom 0.254: v5.08,41.11 10.79,41.11 11.43,41.74 41.27,41.74 43.18,43.65 43.81,43.65 44.45,43.02 49.53,43.02 50.16,42.38 75.56,42.38 78.1,44.92 v86.35,44.92 | v85.08,11.9 84.45,11.9 83.81,11.27 43.81,11.27 43.18,10.63 8.89,10.63 8.25,10 SV1.4
N$12  (via drill 0.61)
  Top 0.254: v6.34,42.38 v6.34,34.76 | v76.83,44.92 85.08,44.92 86.35,46.19 87.62,46.19 87.62,44.92 86.99,44.28 86.99,41.74 86.35,41.11 86.35,23.33 85.08,22.06 85.08,13.17 86.35,11.9 v86.35,3.64
  Bottom 0.254: v6.34,34.76 4.44,34.76 IC2.3 | v6.34,42.38 40.64,42.38 42.54,44.28 44.45,44.28 45.08,43.65 50.16,43.65 50.8,43.02 74.92,43.02 v76.83,44.92 | v86.35,3.64 82.55,3.64 81.27,2.38 53.97,2.38 52.07,4.28 44.45,4.28 43.81,4.92 10.79,4.92 9.52,6.18 9.52,7.46 8.89,8.09 7.62,8.09 6.98,8.73 5.71,8.73 SV1.2
N$13  (via drill 0.61)
  Top 0.254: v6.34,22.06 6.34,10.63 6.98,10 6.98,8.09 6.34,7.46 6.34,6.82 SV1.1
  Bottom 0.254: v6.34,22.06 9.52,22.06 IC2.13
N$14  (via drill 0.61)
  Top 0.254: v5.71,24.6 4.44,25.87 1.27,25.87 1.27,9.36 v2.54,8.09
  Bottom 0.254: v5.71,24.6 9.52,24.6 IC2.14 | v2.54,8.09 6.34,8.09 6.98,7.46 6.98,6.82 7.62,6.82 SV1.3
N$15
  Top 0.254: IC2.17 10.16,31.58 8.89,30.31 8.89,10.63 9.52,10 9.52,8.73 10.79,7.46 SV1.5
N$16  (via drill 0.61)
  Top 0.254: v12.7,48.09 12.7,35.39 12.06,34.76 IC2.18 | v26.66,48.09 26.66,16.98 26.03,16.34 v26.03,6.18
  Bottom 0.254: v26.66,48.09 v12.7,48.09 | v26.03,6.18 25.39,5.55 13.97,5.55 13.33,6.18 SV1.7
N$17
  Top 0.254: IC3.13 22.86,22.7 19.68,25.87 19.04,25.87 19.04,25.23 18.41,24.6 18.41,13.17 17.14,11.9 17.14,8.73 15.87,7.46 SV1.9
N$18  (via drill 0.61)
  Top 0.254: v19.68,44.28 20.95,43.02 20.95,32.22 21.58,31.58 21.58,25.23 22.22,24.6 IC3.14 | v7.62,44.28 7.62,22.06 6.98,21.42 6.98,15.08 v7.62,14.44 | v19.68,14.44 20.31,13.81 20.31,10.63 19.68,10 19.68,8.09 19.04,7.46 19.04,6.82 SV1.11
  Bottom 0.254: v19.68,44.28 19.04,43.65 8.25,43.65 v7.62,44.28 | v7.62,14.44 8.25,15.08 19.04,15.08 v19.68,14.44
N$19  (via drill 0.61)
  Top 0.254: v21.58,43.65 21.58,32.85 22.22,32.22 IC3.17 | v88.26,47.46 88.26,44.28 87.62,43.65 87.62,41.11 86.99,40.48 v86.99,22.7 | v22.22,11.9 22.22,8.09 21.58,7.46 21.58,6.82 SV1.13
  Bottom 0.254: v21.58,43.65 22.22,43.02 40,43.02 41.91,44.92 45.08,44.92 45.72,44.28 50.8,44.28 51.43,43.65 74.29,43.65 78.1,47.46 v88.26,47.46 | v86.99,22.7 106.04,22.7 107.94,20.79 107.94,13.81 85.08,13.81 83.18,11.9 43.18,11.9 42.54,11.27 22.86,11.27 v22.22,11.9
N$20
  Top 0.254: IC3.18 24.12,34.12 25.39,32.85 25.39,9.36 23.49,7.46 SV1.15
N$21
  Top 0.254: C3.1 142.87,6.18 141.6,7.46 141.6,21.42 142.87,22.7 R1.1 143.5,23.33 144.14,23.33 IC18.1
N$22
  Top 0.254: R2.1 143.5,20.79 144.14,20.79 IC18.2 | S1.A 137.79,11.27 139.06,12.54 139.06,16.34 S1.A1
  Bottom 0.254: R2.1 142.87,20.15 139.69,16.98 S1.A1
N$23  (via drill 0.61)
  Top 0.254: IC21.3 102.23,65.88 102.23,64.61 IC21.4 | v111.12,15.71 111.12,39.84 111.75,40.48 111.75,62.06 v111.12,62.7
  Bottom 0.254: v111.12,15.71 113.66,15.71 IC27.5 | v111.12,62.7 110.48,63.34 102.86,63.34 IC21.4
N$24  (via drill 0.61)
  Top 0.254: v46.98,53.81 46.98,78.58 47.62,79.21 IC26.2 | v73.66,53.81 73.66,59.52 v75.56,61.43
  Bottom 0.254: v46.98,53.81 53.97,53.81 54.61,54.45 73.02,54.45 v73.66,53.81 | v75.56,61.43 78.1,61.43 IC24.10
N$25  (via drill 0.61)
  Top 0.254: v45.72,76.67 46.35,76.03 46.35,54.45 45.72,53.81 v45.72,50 | v70.48,50 v70.48,58.25
  Bottom 0.254: v45.72,76.67 47.62,76.67 IC26.3 | v45.72,50 53.34,50 53.97,50.63 69.84,50.63 v70.48,50 | v70.48,58.25 70.48,58.89 78.1,58.89 IC24.11
N$26
  Top 0.254: IC13.2 86.35,93.81 85.08,92.55 85.08,74.77 86.99,72.86 86.99,63.97 84.45,61.43 83.18,61.43 83.18,71.59 81.91,72.86 81.91,88.1 82.55,88.73 82.55,93.81 81.27,95.08 81.27,105.25 80.64,105.88 77.46,105.88 77.46,115.41 78.1,116.04 80.64,116.04 80.64,120.48 81.91,121.75 SV7.2
  Bottom 0.254: IC11.2 62.86,94.45 63.5,95.08 64.77,95.08 65.4,95.72 84.45,95.72 85.72,94.45 IC13.2 | SV6.2 57.15,122.39 58.41,123.66 75.56,123.66 76.83,122.39 81.27,122.39 SV7.2
N$27
  Top 0.254: C6.1 125.09,7.46 123.82,6.18 123.82,4.92 123.19,4.28 111.75,4.28 111.75,6.18 111.12,6.82 111.12,9.36 114.3,12.54 IC27.6 114.3,13.81 112.39,15.71 112.39,19.52 R11.A 113.02,21.42 114.3,22.7 IC27.2
N$28
  Top 0.254: IC27.1 115.56,25.23 116.83,23.96 116.83,9.36 115.56,8.09 R9.1
  Bottom 0.254: R9.1 115.56,8.09 118.1,5.55 121.91,5.55 R10.2
N$29
  Top 0.254: IC9.3 40.64,34.12 39.37,32.85 39.37,14.44 41.27,12.54 41.27,10 SV2.10
N$30  (via drill 0.61)
  Top 0.254: v43.18,42.38 43.18,32.85 42.54,32.22 IC9.4 | v85.08,42.38 85.08,24.6 83.81,23.33 83.81,11.27 v84.45,10.63
  Bottom 0.254: v43.18,42.38 48.89,42.38 49.53,41.74 77.46,41.74 78.1,42.38 v85.08,42.38 | v84.45,10.63 44.45,10.63 43.81,10 SV2.12
N$31  (via drill 0.61)
  Top 0.254: v45.08,24.6 45.08,21.42 46.35,20.15 46.35,10 SV2.14
  Bottom 0.254: v45.08,24.6 42.54,24.6 IC9.7
N$32  (via drill 0.61)
  Top 0.254: v46.35,21.42 46.98,20.79 46.98,15.08 48.89,13.17 48.89,10 SV2.16
  Bottom 0.254: v46.35,21.42 41.91,21.42 IC9.8
N$33
  Top 0.254: IC8.12 29.84,112.23 31.11,113.5 31.11,119.22 SV4.1
N$34  (via drill 0.61)
  Top 0.254: v31.74,104.61 31.74,115.41 33.65,117.31 33.65,119.22 SV4.3
  Bottom 0.254: v31.74,104.61 29.84,104.61 IC8.15
N$35  (via drill 0.61)
  Top 0.254: v36.19,116.67 36.19,119.22 SV4.5 | v29.84,117.31 30.47,116.67 30.47,114.14 29.84,113.5 26.66,113.5 26.66,102.7 27.3,102.07 IC8.16
  Bottom 0.254: v36.19,116.67 30.47,116.67 v29.84,117.31
N$36
  Top 0.254: IC8.19 27.93,93.81 26.66,92.55 26.66,86.83 27.93,85.56 27.93,76.03 27.3,75.4 24.12,75.4 24.12,68.41 24.76,67.78 34.92,67.78 34.92,90.64 34.29,91.28 34.29,102.7 34.92,103.34 37.46,103.34 38.73,104.61 38.73,119.22 SV4.7
N$37  (via drill 0.61)
  Top 0.254: v30.47,45.55 30.47,35.39 29.84,34.76 IC4.3 | v70.48,25.87 v70.48,44.92
  Bottom 0.254: v30.47,45.55 45.72,45.55 46.35,44.92 51.43,44.92 52.07,44.28 69.84,44.28 v70.48,44.92 | v70.48,25.87 85.08,25.87 87.62,23.33 106.67,23.33 108.58,21.42 108.58,13.17 88.26,13.17 83.18,8.09 68.57,8.09 67.94,7.46 67.94,6.18 66.67,4.92 45.08,4.92 44.45,5.55 35.55,5.55 34.92,6.18 34.92,7.46 34.29,8.09 33.02,8.09 32.38,8.73 31.11,8.73 SV2.2
N$38  (via drill 0.61)
  Top 0.254: v33.65,32.22 33.65,10 SV2.4
  Bottom 0.254: v33.65,32.22 29.84,32.22 IC4.4
N$39
  Top 0.254: IC4.7 29.2,23.96 30.47,22.7 30.47,11.9 29.2,10.63 29.2,5.55 29.84,4.92 37.46,4.92 37.46,7.46 36.19,8.73 SV2.6
N$40  (via drill 0.61)
  Top 0.254: v38.1,20.79 38.73,20.15 38.73,10 SV2.8
  Bottom 0.254: v38.1,20.79 31.11,20.79 30.47,21.42 29.2,21.42 IC4.8
N$41
  Top 0.254: IC9.13 48.26,22.7 45.08,25.87 43.18,25.87 43.18,23.96 42.54,23.33 43.18,22.7 43.18,13.81 42.54,13.17 42.54,8.73 41.27,7.46 SV2.9
N$42  (via drill 0.61)
  Top 0.254: v46.98,33.49 46.98,25.23 47.62,24.6 IC9.14 | v82.55,2.38 v82.55,33.49 | v43.81,3.64 43.81,6.18 SV2.11
  Bottom 0.254: v82.55,33.49 v46.98,33.49 | v82.55,2.38 81.91,1.74 53.34,1.74 51.43,3.64 v43.81,3.64
N$43  (via drill 0.61)
  Top 0.254: v53.97,3.64 v53.97,6.18 | v81.27,6.82 v81.27,3.64
  Bottom 0.254: v53.97,6.18 53.34,5.55 46.98,5.55 46.35,6.18 SV2.13 | v53.97,3.64 54.61,3.01 80.64,3.01 v81.27,3.64 | v81.27,6.82 81.91,7.46 83.81,7.46 88.89,12.54 107.94,12.54 109.21,11.27 113.02,11.27 113.66,11.9 118.1,11.9 120.64,14.44 130.81,14.44 133.98,17.61 133.98,18.88 130.81,22.06 121.28,22.06 118.74,24.6 118.74,29.04 120.64,29.04 125.72,34.12 125.72,37.94 125.09,37.94 122.55,40.48 118.1,40.48 117.47,41.11 99.05,41.11 97.78,42.38 93.34,42.38 89.53,46.19 89.53,50 74.29,50 69.21,44.92 52.7,44.92 52.07,45.55 46.98,45.55 46.35,46.19 31.11,46.19 30.47,46.82 23.49,46.82 19.68,43.02 6.98,43.02 6.34,43.65 4.44,43.65 1.27,40.48 1.27,36.03 6.34,36.03 8.89,33.49 43.18,33.49 44.45,32.22 47.62,32.22 IC9.17
N$44
  Top 0.254: IC9.18 49.53,34.12 50.8,32.85 50.8,9.36 48.89,7.46 SV2.15
N$45  (via drill 0.61)
  Top 0.254: v32.38,22.06 32.38,8.09 31.74,7.46 31.74,6.82 SV2.1
  Bottom 0.254: v32.38,22.06 34.92,22.06 IC4.13
N$46
  Top 0.254: IC4.14 36.83,25.23 38.1,26.5 38.1,32.85 37.46,33.49 31.11,33.49 31.11,11.27 29.84,10 29.84,6.18 30.47,5.55 33.02,5.55 33.02,6.82 SV2.3
N$47
  Top 0.254: IC4.17 35.55,31.58 34.29,30.31 34.29,10.63 34.92,10 34.92,8.73 36.19,7.46 SV2.5
N$48  (via drill 0.61)
  Top 0.254: v38.1,23.33 38.73,23.96 38.73,33.49 37.46,34.76 IC4.18 | v43.81,13.17 v43.81,23.33 | v40,12.54 40,8.09 39.37,7.46 39.37,6.82 SV2.7
  Bottom 0.254: v43.81,23.33 v38.1,23.33 | v43.81,13.17 43.81,12.54 v40,12.54
N$49  (via drill 0.61)
  Top 0.254: v42.54,123.66 42.54,119.22 43.18,118.58 43.18,106.52 42.54,105.88 40,105.88 39.37,105.25 39.37,103.97 37.46,102.07 IC8.5
  Bottom 0.254: v42.54,123.66 34.29,123.66 33.65,123.03 SV4.4
N$50
  Top 0.254: IC8.6 36.83,105.25 38.1,106.52 38.1,110.33 37.46,110.96 34.29,110.96 34.29,118.58 34.92,119.22 34.92,120.48 36.19,121.75 SV4.6
N$51  (via drill 0.61)
  Top 0.254: v53.34,116.67 53.34,119.22 53.97,119.85 53.97,126.2 33.02,126.2 31.11,124.3 31.11,123.03 SV4.2 | v57.15,110.96 56.51,110.96 56.51,102.07 57.78,100.8 v57.78,90.64 | v37.46,90 38.1,90.64 38.1,93.81 37.46,94.45 IC8.2
  Bottom 0.254: v53.34,116.67 52.07,115.41 52.07,111.59 52.7,110.96 v57.15,110.96 | v57.78,90.64 57.15,90.64 56.51,90 v37.46,90
N$52
  Top 0.254: IC8.9 36.83,112.86 38.1,114.14 38.1,118.58 37.46,119.22 37.46,120.48 38.73,121.75 SV4.8
N$53
  Top 0.254: IC6.12 3.8,112.86 5.71,114.77 5.71,119.22 SV3.1
N$54  (via drill 0.61)
  Top 0.254: v8.25,104.61 8.25,119.22 SV3.3
  Bottom 0.254: v8.25,104.61 4.44,104.61 IC6.15
N$55
  Top 0.254: IC6.16 2.54,102.7 1.27,103.97 1.27,122.39 2.54,123.66 12.06,123.66 12.06,121.75 10.79,120.48 SV3.5
N$56  (via drill 0.61)
  Top 0.254: v13.33,93.18 13.33,119.22 SV3.7
  Bottom 0.254: v13.33,93.18 4.44,93.18 3.8,93.81 IC6.19
N$57  (via drill 0.61)
  Top 0.254: v5.71,94.45 v5.71,112.23 | v2.54,117.94 v2.54,122.39
  Bottom 0.254: v5.71,94.45 9.52,94.45 IC6.2 | v5.71,112.23 4.44,113.5 1.9,113.5 1.27,114.14 1.27,117.94 v2.54,117.94 | v2.54,122.39 5.08,122.39 SV3.2
N$58  (via drill 0.61)
  Top 0.254: v6.98,102.07 6.98,104.61 7.62,105.25 7.62,118.58 6.98,119.22 6.98,120.48 7.62,121.12 8.25,121.12 8.25,121.75 SV3.4
  Bottom 0.254: v6.98,102.07 9.52,102.07 IC6.5
N$59
  Top 0.254: IC6.6 10.16,105.25 8.89,106.52 8.89,118.58 9.52,119.22 9.52,120.48 10.79,121.75 SV3.6
N$60
  Top 0.254: IC6.9 11.43,112.86 12.7,114.14 12.7,118.58 12.06,119.22 12.06,120.48 13.33,121.75 SV3.8
N$61  (via drill 0.61)
  Top 0.254: v17.14,117.31 17.77,116.67 17.77,106.52 17.14,105.88 14.6,105.88 13.97,105.25 13.97,95.08 14.6,94.45 IC7.19 | v23.49,117.31 23.49,119.22 SV3.15
  Bottom 0.254: v17.14,117.31 v23.49,117.31
N$62  (via drill 0.61)
  Top 0.254: v20.95,102.7 20.95,119.22 SV3.13
  Bottom 0.254: v20.95,102.7 16.5,102.7 IC7.16
N$63  (via drill 0.61)
  Top 0.254: v32.38,117.94 v32.38,123.66 | v110.48,113.5 109.85,112.86 109.85,96.36 110.48,95.72 v110.48,83.02
  Bottom 0.254: v32.38,123.66 17.14,123.66 17.14,121.75 18.41,120.48 SV3.11 | v32.38,117.94 67.3,117.94 67.94,118.58 68.57,117.94 73.66,117.94 74.29,118.58 87.62,118.58 88.26,117.94 101.59,117.94 106.04,113.5 v110.48,113.5 | v110.48,83.02 89.53,83.02 86.99,85.56 71.75,85.56 69.21,88.1 52.07,88.1 50.8,86.83 39.37,86.83 38.73,87.47 26.03,87.47 25.39,86.83 20.31,86.83 19.04,88.1 15.87,88.1 15.24,88.73 3.8,88.73 3.17,88.1 2.54,88.1 1.27,89.37 1.27,100.8 12.7,100.8 13.97,102.07 13.97,104.61 14.6,104.61 IC7.15
N$64
  Top 0.254: IC7.12 15.24,112.86 13.97,114.14 13.97,117.31 15.87,119.22 SV3.9
N$65  (via drill 0.61)
  Top 0.254: v15.87,125.56 15.87,123.03 SV3.10 | v104.77,125.56 104.77,119.85 104.13,119.22 104.13,96.99 104.77,96.36 104.77,91.28 v104.13,90.64 | v75.56,75.4 74.29,74.13 74.29,71.59 73.02,70.32 68.57,70.32 66.03,72.86 66.03,79.84 65.4,80.48 62.23,80.48 62.23,90 63.5,91.28 63.5,92.55 62.86,93.18 60.32,93.18 59.05,91.91 59.05,83.66 58.41,83.02 58.41,63.34 57.78,62.7 58.41,62.06 58.41,60.8 57.78,60.16 54.61,60.16 54.61,55.71 55.88,54.45 55.88,36.66 55.24,36.03 44.45,36.03 44.45,42.38 33.65,53.17 27.93,53.17 26.66,51.91 17.77,51.91 17.77,75.4 19.04,76.67 19.04,84.29 21.58,86.83 21.58,93.81 22.22,94.45 IC7.2
  Bottom 0.254: v15.87,125.56 16.5,126.2 104.13,126.2 v104.77,125.56 | v104.13,90.64 111.75,90.64 117.47,84.92 125.72,84.92 126.36,85.56 128.9,85.56 137.16,77.3 137.16,76.03 136.52,76.03 135.88,75.4 135.25,75.4 134.62,76.03 129.53,76.03 128.9,75.4 v75.56,75.4
N$66
  Top 0.254: IC7.5 22.86,102.7 21.58,103.97 21.58,118.58 22.22,119.22 22.22,123.03 21.58,123.66 18.41,123.66 18.41,123.03 SV3.12
N$67  (via drill 0.61)
  Top 0.254: v19.04,104.61 19.68,105.25 19.68,116.04 17.14,118.58 17.14,120.48 17.77,121.12 19.04,121.12 20.31,122.39 SV3.14
  Bottom 0.254: v19.04,104.61 22.22,104.61 IC7.6
N$68
  Top 0.254: IC7.9 24.12,112.86 25.39,114.14 25.39,119.85 23.49,121.75 SV3.16
N$69  (via drill 0.61)
  Top 0.254: v50.8,88.1 50.8,93.81 50.16,94.45 IC10.2 | v97.78,86.19 97.15,86.83 97.15,99.53 98.42,100.8 102.86,100.8 102.86,119.22 102.23,119.85 v102.23,123.03 | v43.81,124.3 43.18,124.3 42.54,124.93 41.27,124.93 41.27,123.03 SV4.10
  Bottom 0.254: v50.8,88.1 51.43,88.73 69.84,88.73 71.75,86.83 88.89,86.83 89.53,86.19 v97.78,86.19 | v102.23,123.03 101.59,123.66 92.7,123.66 91.44,124.93 44.45,124.93 v43.81,124.3
N$70  (via drill 0.61)
  Top 0.254: v47.62,121.12 47.62,119.22 46.98,118.58 46.98,103.34 47.62,102.7 47.62,102.07 IC10.5
  Bottom 0.254: v47.62,121.12 44.45,121.12 43.81,121.75 SV4.12
N$71  (via drill 0.61)
  Top 0.254: v44.45,104.61 44.45,118.58 45.08,119.22 45.08,121.75 45.72,122.39 SV4.14
  Bottom 0.254: v44.45,104.61 47.62,104.61 IC10.6
N$72
  Top 0.254: IC10.9 49.53,112.86 50.8,114.14 50.8,119.85 48.89,121.75 SV4.16
N$73  (via drill 0.61)
  Top 0.254: v43.81,100.8 43.81,95.72 42.54,94.45 IC10.19 | v51.43,101.44 52.07,102.07 52.07,102.7 52.7,103.34 52.07,103.97 52.07,119.22 v52.7,119.85
  Bottom 0.254: v43.81,100.8 50.8,100.8 v51.43,101.44 | v52.7,119.85 49.53,119.85 SV4.15
N$74
  Top 0.254: IC10.16 42.54,102.07 45.72,102.07 45.72,119.85 SV4.13
N$75
  Top 0.254: IC10.15 42.54,104.61 43.81,105.88 43.81,119.22 SV4.11
N$76
  Top 0.254: IC10.12 40.64,112.86 39.37,114.14 39.37,117.31 41.27,119.22 SV4.9
N$77
  Top 0.254: IC16.3 66.03,34.12 64.77,32.85 64.77,11.9 66.67,10 SV5.10
N$78  (via drill 0.61)
  Top 0.254: v77.46,22.06 v77.46,30.95 | v69.84,18.25 69.21,17.61 69.21,10 SV5.12
  Bottom 0.254: v77.46,30.95 69.21,30.95 68.57,31.58 67.3,31.58 IC16.4 | v77.46,22.06 76.19,20.79 76.19,18.88 75.56,18.25 v69.84,18.25
N$79
  Top 0.254: IC16.7 67.94,24.6 70.48,24.6 70.48,18.88 71.75,17.61 71.75,10 SV5.14
N$80  (via drill 0.61)
  Top 0.254: v71.75,21.42 72.38,20.79 72.38,15.08 74.29,13.17 74.29,10 SV5.16
  Bottom 0.254: v71.75,21.42 67.3,21.42 IC16.8
N$81
  Top 0.254: IC11.12 54.61,112.86 56.51,114.77 56.51,119.22 SV6.1
N$82  (via drill 0.61)
  Top 0.254: v59.05,104.61 59.05,119.22 SV6.3
  Bottom 0.254: v59.05,104.61 55.24,104.61 IC11.15
N$83  (via drill 0.61)
  Top 0.254: v57.78,102.07 57.78,104.61 58.41,105.25 58.41,116.04 v57.78,116.67 | v61.59,116.67 61.59,119.22 SV6.5
  Bottom 0.254: v57.78,102.07 55.24,102.07 IC11.16 | v57.78,116.67 v61.59,116.67
N$84  (via drill 0.61)
  Top 0.254: v56.51,100.8 56.51,95.72 55.24,94.45 IC11.19 | v63.5,100.8 64.13,101.44 64.13,119.22 SV6.7
  Bottom 0.254: v56.51,100.8 v63.5,100.8
N$85
  Top 0.254: IC13.12 80,112.86 81.91,114.77 81.91,119.22 SV7.1
N$86  (via drill 0.61)
  Top 0.254: v84.45,104.61 84.45,119.22 SV7.3
  Bottom 0.254: v84.45,104.61 80.64,104.61 IC13.15
N$87  (via drill 0.61)
  Top 0.254: v83.18,102.07 83.18,104.61 83.81,105.25 83.81,116.04 v83.18,116.67 | v86.99,116.67 86.99,119.22 SV7.5
  Bottom 0.254: v83.18,102.07 80.64,102.07 IC13.16 | v83.18,116.67 v86.99,116.67
N$88  (via drill 0.61)
  Top 0.254: v90.16,88.1 90.16,94.45 89.53,95.08 89.53,109.69 90.8,110.96 93.34,110.96 93.97,111.59 93.97,115.41 93.34,116.04 93.34,120.48 92.7,121.12 91.44,121.12 90.16,119.85 SV7.7 | v81.27,88.73 81.27,93.81 80.64,94.45 IC13.19
  Bottom 0.254: v90.16,88.1 86.99,88.1 86.35,88.73 v81.27,88.73
N$89  (via drill 0.61)
  Top 0.254: v51.43,103.34 v51.43,121.75
  Bottom 0.254: v51.43,103.34 60.32,103.34 60.96,102.7 IC11.5 | v51.43,121.75 52.07,121.12 58.41,121.12 59.05,121.75 SV6.4
N$90
  Top 0.254: IC11.6 60.96,105.25 59.69,106.52 59.69,118.58 60.32,119.22 60.32,120.48 61.59,121.75 SV6.6
N$91
  Top 0.254: IC11.9 62.23,112.86 63.5,114.14 63.5,118.58 62.86,119.22 62.86,120.48 64.13,121.75 SV6.8
N$92
  Top 0.254: IC12.12 66.03,112.86 64.77,114.14 64.77,117.31 66.67,119.22 SV6.9
N$93
  Top 0.254: IC12.15 67.94,104.61 69.21,105.88 69.21,119.22 SV6.11
N$94  (via drill 0.61)
  Top 0.254: v60.32,72.86 60.96,72.22 v60.96,56.98
  Bottom 0.254: v60.32,72.86 55.24,72.86 54.61,73.5 49.53,73.5 IC26.4 | v60.96,56.98 61.59,56.35 78.1,56.35 IC24.12
N$95
  Top 0.254: IC12.16 67.94,102.07 71.11,102.07 71.11,119.85 SV6.13
N$96  (via drill 0.61)
  Top 0.254: v67.94,117.31 68.57,116.67 68.57,106.52 67.94,105.88 65.4,105.88 64.77,105.25 64.77,95.08 65.4,94.45 IC12.19 | v74.29,117.31 74.29,119.22 SV6.15
  Bottom 0.254: v67.94,117.31 v74.29,117.31
N$97  (via drill 0.61)
  Top 0.254: v79.37,117.31 79.37,126.2 71.11,126.2 67.3,122.39 SV6.10 | v105.41,110.96 104.77,110.33 104.77,97.62 105.41,96.99 105.41,88.73 106.04,88.1 106.04,83.02 104.77,81.75 v104.77,79.21 | v76.83,77.94 76.83,99.53 75.56,100.8 72.38,100.8 72.38,95.08 73.02,94.45 IC12.2
  Bottom 0.254: v79.37,117.31 80,117.94 86.99,117.94 87.62,117.31 100.96,117.31 105.41,112.86 v105.41,110.96 | v104.77,79.21 97.15,79.21 95.88,77.94 v76.83,77.94
N$98
  Top 0.254: IC12.5 73.66,102.7 72.38,103.97 72.38,118.58 73.02,119.22 73.02,123.03 72.38,123.66 69.84,123.66 69.84,122.39 SV6.12
N$99  (via drill 0.61)
  Top 0.254: v69.84,104.61 69.84,118.58 70.48,119.22 70.48,121.75 71.11,122.39 SV6.14
  Bottom 0.254: v69.84,104.61 73.02,104.61 IC12.6
N$100
  Top 0.254: IC12.9 74.92,112.86 76.19,114.14 76.19,119.85 74.29,121.75 SV6.16
N$101
  Top 0.254: IC15.3 54.61,34.12 56.51,32.22 56.51,13.81 57.15,13.17 57.15,9.36 SV5.2
N$102  (via drill 0.61)
  Top 0.254: v59.05,32.22 59.05,10 SV5.4
  Bottom 0.254: v59.05,32.22 55.24,32.22 IC15.4
N$103  (via drill 0.61)
  Top 0.254: v55.88,13.17 55.88,23.96 55.24,24.6 IC15.7 | v61.59,13.17 61.59,10 SV5.6
  Bottom 0.254: v55.88,13.17 v61.59,13.17
N$104
  Top 0.254: IC15.8 53.34,21.42 52.07,20.15 52.07,10.63 55.24,7.46 55.24,6.18 55.88,5.55 65.4,5.55 65.4,7.46 64.13,8.73 SV5.8
N$105  (via drill 0.61)
  Top 0.254: v69.21,22.7 68.57,22.06 68.57,10.63 67.94,10 67.94,8.09 67.3,7.46 67.3,6.82 SV5.9
  Bottom 0.254: v69.21,22.7 73.66,22.7 IC16.13
N$106  (via drill 0.61)
  Top 0.254: v83.81,24.6 83.18,23.96 83.18,5.55 v83.81,4.92 | v69.21,4.92 69.21,6.18 SV5.11
  Bottom 0.254: v83.81,24.6 75.56,24.6 IC16.14 | v69.21,4.92 v83.81,4.92
N$107  (via drill 0.61)
  Top 0.254: v98.42,32.22 98.42,22.06 99.05,21.42 v99.05,6.18
  Bottom 0.254: v98.42,32.22 75.56,32.22 IC16.17 | v99.05,6.18 83.81,6.18 83.18,5.55 72.38,5.55 71.75,6.18 SV5.13
N$108
  Top 0.254: IC16.18 74.92,34.12 76.19,32.85 76.19,9.36 74.29,7.46 SV5.15
N$109  (via drill 0.61)
  Top 0.254: v57.78,22.06 57.78,8.09 57.15,7.46 57.15,6.82 SV5.1
  Bottom 0.254: v57.78,22.06 60.32,22.06 IC15.13
N$110  (via drill 0.61)
  Top 0.254: v52.07,23.33 51.43,22.7 51.43,10 v52.07,9.36
  Bottom 0.254: v52.07,23.33 55.24,23.33 56.51,24.6 60.32,24.6 IC15.14 | v52.07,9.36 52.7,8.73 53.97,8.73 54.61,8.09 57.15,8.09 57.78,7.46 57.78,6.82 58.41,6.82 SV5.3
N$111
  Top 0.254: IC15.17 60.96,31.58 59.69,30.31 59.69,10.63 60.32,10 60.32,8.73 61.59,7.46 SV5.5
N$112  (via drill 0.61)
  Top 0.254: v62.86,13.17 62.86,7.46 63.5,6.82 SV5.7 | v94.61,15.08 94.61,18.88 93.34,20.15 93.34,21.42 92.7,22.06 92.7,36.66 93.34,37.3 89.53,41.11 89.53,47.46 v85.72,51.27 | v65.4,58.89 63.5,56.98 63.5,35.39 62.86,34.76 IC15.18
  Bottom 0.254: v62.86,13.17 63.5,12.54 82.55,12.54 84.45,14.44 93.97,14.44 v94.61,15.08 | v85.72,51.27 92.07,57.62 92.07,60.16 74.29,60.16 73.66,59.52 69.84,59.52 69.21,58.89 v65.4,58.89
N$113  (via drill 0.61)
  Top 0.254: v103.5,95.72 v103.5,119.85
  Bottom 0.254: v103.5,95.72 94.61,95.72 93.97,95.08 92.7,95.08 IC14.19 | v103.5,119.85 100.32,119.85 SV7.15
N$114
  Top 0.254: IC14.16 93.34,102.07 96.52,102.07 96.52,119.85 SV7.13
N$115
  Top 0.254: IC14.15 92.7,105.25 94.61,107.15 94.61,119.22 SV7.11
N$116
  Top 0.254: IC14.12 91.44,112.86 90.16,114.14 90.16,117.31 92.07,119.22 SV7.9
N$117  (via drill 0.61)
  Top 0.254: v109.21,95.72 v109.21,118.58
  Bottom 0.254: v109.21,95.72 106.04,95.72 104.77,94.45 100.96,94.45 IC14.2 | v109.21,118.58 93.97,118.58 93.34,119.22 93.34,120.48 92.07,121.75 SV7.10
N$118
  Top 0.254: IC14.5 99.05,102.7 97.78,103.97 97.78,118.58 98.42,119.22 98.42,123.03 97.78,123.66 94.61,123.66 94.61,123.03 SV7.12
N$119  (via drill 0.61)
  Top 0.254: v95.24,104.61 95.24,118.58 95.88,119.22 95.88,121.75 96.52,122.39 SV7.14
  Bottom 0.254: v95.24,104.61 98.42,104.61 IC14.6
N$120
  Top 0.254: IC14.9 100.32,112.86 101.59,114.14 101.59,119.85 99.69,121.75 SV7.16
N$121
  Top 0.254: IC13.9 87.62,112.86 88.89,114.14 88.89,118.58 88.26,119.22 88.26,120.48 89.53,121.75 SV7.8
N$122
  Top 0.254: IC13.6 86.35,105.25 85.08,106.52 85.08,118.58 85.72,119.22 85.72,120.48 86.99,121.75 SV7.6
N$123  (via drill 0.61)
  Top 0.254: v76.83,103.34 v76.83,123.66
  Bottom 0.254: v76.83,103.34 85.72,103.34 86.35,102.7 IC13.5 | v76.83,123.66 83.81,123.66 84.45,123.03 SV7.4
N$124  (via drill 0.61)
  Top 0.254: v50.8,56.35 50.8,70.95 50.16,71.59 IC26.5
  Bottom 0.254: v50.8,56.35 60.32,56.35 60.96,55.71 74.92,55.71 76.83,53.81 78.1,53.81 IC24.13
N$125  (via drill 0.61)
  Top 0.254: v52.07,68.41 51.43,67.78 51.43,56.98 52.07,56.35 v52.07,51.27
  Bottom 0.254: v52.07,68.41 49.53,68.41 IC26.6 | v52.07,51.27 78.1,51.27 IC24.14
N$126  (via drill 0.61)
  Top 0.254: v52.7,65.24 52.07,64.61 52.07,57.62 52.7,56.98 52.7,53.17 v53.34,52.54 | v76.83,52.54 v76.83,48.73
  Bottom 0.254: v52.7,65.24 52.07,65.88 49.53,65.88 IC26.7 | v53.34,52.54 53.97,51.91 76.19,51.91 v76.83,52.54 | v76.83,48.73 78.1,48.73 IC24.15
N$127  (via drill 0.61)
  Top 0.254: v59.05,62.7 v59.05,58.25 | v90.8,57.62 90.8,43.65 v91.44,43.02
  Bottom 0.254: v59.05,62.7 55.24,62.7 54.61,63.34 52.07,63.34 51.43,63.97 50.16,63.97 IC26.8 | v59.05,58.25 60.96,58.25 62.23,56.98 77.46,56.98 78.1,57.62 v90.8,57.62 | v91.44,43.02 88.26,46.19 80.64,46.19 IC24.16
N$128  (via drill 0.61)
  Top 0.254: v53.97,55.08 v53.97,61.43 | v74.92,54.45 74.92,45.55 76.83,43.65 78.1,43.65 IC24.17
  Bottom 0.254: v53.97,61.43 50.16,61.43 IC26.9 | v53.97,55.08 74.29,55.08 v74.92,54.45
N$129
  Bottom 0.254: IC25.3 65.4,79.21 66.67,80.48 73.66,80.48 74.92,79.21 78.1,79.21 IC24.3
N$130
  Bottom 0.254: IC25.4 65.4,76.67 66.67,77.94 75.56,77.94 76.83,76.67 78.1,76.67 IC24.4
N$131
  Bottom 0.254: IC25.5 65.4,74.13 66.67,75.4 74.29,75.4 75.56,74.13 78.1,74.13 IC24.5
N$132
  Bottom 0.254: IC25.6 65.4,71.59 66.03,72.22 67.94,72.22 68.57,72.86 76.83,72.86 78.1,71.59 IC24.6
N$133
  Bottom 0.254: IC25.7 65.4,69.05 66.67,70.32 76.19,70.32 77.46,69.05 78.1,69.05 IC24.7
N$134
  Bottom 0.254: IC25.8 65.4,66.51 66.67,67.78 76.83,67.78 78.1,66.51 IC24.8
N$135
  Bottom 0.254: IC25.9 65.4,63.97 66.67,65.24 76.83,65.24 78.1,63.97 IC24.9
N$136  (via drill 0.61)
  Top 0.254: v73.02,50 74.29,48.73 74.29,44.92 76.83,42.38 76.83,39.84 78.1,38.57 IC24.19 | v44.45,48.73 44.45,50 45.08,50.63 45.08,54.45 45.72,55.08 45.72,75.4 44.45,76.67 v44.45,81.75
  Bottom 0.254: v73.02,50 71.75,48.73 70.48,48.73 69.21,50 54.61,50 53.97,49.37 46.35,49.37 45.72,48.73 v44.45,48.73 | v44.45,81.75 47.62,81.75 IC26.1
N$137  (via drill 0.61)
  Top 0.254: v68.57,85.56 69.21,84.92 69.21,79.21 69.84,78.58 69.84,76.03 70.48,75.4 73.02,75.4 74.29,76.67 74.29,79.84 v74.92,80.48
  Bottom 0.254: v68.57,85.56 65.4,85.56 64.77,84.92 IC25.1 | v74.92,80.48 88.89,80.48 90.16,81.75 93.34,81.75 IC24.39
N$138  (via drill 0.61)
  Top 0.254: v121.28,52.54 121.28,29.68 118.74,27.14 118.74,15.71 119.38,15.08 119.38,13.17 118.74,12.54 118.74,7.46 119.38,6.82 120.01,6.82 121.28,8.09 120.64,8.73 120.64,12.54 121.28,13.17 IC27.9 | v107.31,52.54 107.94,53.17 107.94,62.06 108.58,62.7 v108.58,85.56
